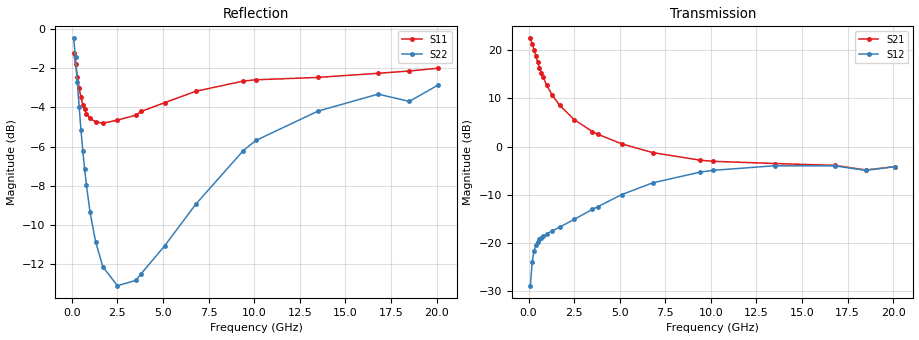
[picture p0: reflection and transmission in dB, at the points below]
!  Infineon Technologies AG
! BFR380L3 , PF131585-7, No.6, Th 09.10.01, soldered on pcb-board, measured with PP GSG850
!  Vce=1.0 V,  Ic=4.0 mA
! Common Emitter S-Parameters:  15. November 2001
#  GHz  S  MA  R  50
! f  S11  S21  S12  S22
! GHz  Mag  Ang  Mag  Ang  Mag  Ang  Mag  Ang
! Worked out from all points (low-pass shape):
!   201 points, 100 MHz to 20.1 GHz, reference 50 ohm
!   highest |S21| = 22.49 dB at 100 MHz (marker M1); lowest = -4.9 dB at 18.5 GHz (marker M2)
!   |S21| within 3 dB of the highest: start of sweep to 350.5 MHz
!   lowest |S11| = -4.8 dB at 1.7 GHz (marker M3), VSWR 3.71, Z = 13.5 - j1.94 ohm
!   |S11| at or under -10 dB: nowhere
!   |S22| runs from -13.2 to -0.5 dB; largest |S21 - S12| = 13
!   S11 on the Smith chart (normalised r, x): 100 MHz: 1.02, -3.58; 400 MHz: 0.32, -0.90; 1 GHz: 0.28, -0.27; 3.8 GHz: 0.26, +0.32; 9.4 GHz: 0.34, +1.10; 20.1 GHz: 0.97, +2.58
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0.1  0.8714 -29.1  13.32 161.1  0.03582 74.0  0.9485 -18.4
0.2  0.8161 -54.6  11.76 145.0  0.06331 62.0  0.8475 -33.9
0.3  0.757 -76.1  10.17 132.3  0.08193 52.9  0.7331 -45.9
0.4  0.7068 -93.1  8.749 122.4  0.09407 46.5  0.6333 -55.0
0.5  0.6695 -106.7  7.564 114.7  0.1026 42.5  0.5528 -62.0
0.6  0.6409 -118.1  6.622 108.6  0.1086 39.7  0.4894 -67.6
0.7  0.6235 -127.5  5.871 103.3  0.1134 37.9  0.4386 -72.2
0.8  0.6081 -135.1  5.254 98.9  0.1172 36.9  0.3985 -76.0
1  0.5916 -147.6  4.335 91.6  0.1237 36.0  0.3398 -82.4
1.3  0.5802 -161.7  3.431 82.9  0.1328 36.4  0.286 -90.2
1.7  0.575 -175.2  2.691 73.4  0.1452 38.4  0.2464 -99.0
2.5  0.5856 165.2  1.907 58.1  0.1749 42.4  0.2205 -114.6
3.5  0.6028 146.8  1.432 42.6  0.2226 44.9  0.2274 -132.9
3.8  0.6164 142.2  1.343 38.8  0.2369 45.0  0.2366 -139.4
5.1  0.6494 123.9  1.069 23.5  0.3163 42.0  0.2794 -161.5
6.8  0.6942 103.9  0.8664 9.2  0.4192 33.3  0.3568 170.6
9.400001  0.7374 81.6  0.7226 -4.5  0.5421 15.9  0.4892 137.7
10.1  0.7429 76.7  0.7029 -7.5  0.566 11.1  0.5196 129.7
13.5  0.7534 58.8  0.6666 -21.0  0.6319 -10.8  0.6177 98.2
16.8  0.772 47.0  0.6379 -32.5  0.6296 -26.9  0.6827 75.9
18.5  0.7824 45.3  0.571 -40.2  0.5656 -35.3  0.6538 70.4
20.1  0.7955 38.0  0.62 -43.8  0.6183 -40.3  0.7211 59.6
